VERSION 5.7 ;
  NOWIREEXTENSIONATPIN ON ;
  DIVIDERCHAR "/" ;
  BUSBITCHARS "[]" ;
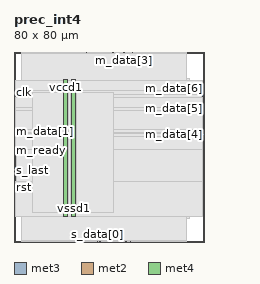
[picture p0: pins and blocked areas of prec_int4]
MACRO prec_int4
  CLASS BLOCK ;
  FOREIGN prec_int4 ;
  ORIGIN 0.000 0.000 ;
  SIZE 80.000 BY 80.000 ;
  PIN clk
    DIRECTION INPUT ;
    USE SIGNAL ;
    ANTENNAGATEAREA 1.286700 ;
    ANTENNADIFFAREA 0.434700 ;
    PORT
      LAYER met3 ;
        RECT 0.000 62.600 0.600 63.200 ;
    END
  END clk
  PIN m_data[0]
    DIRECTION OUTPUT ;
    USE SIGNAL ;
    ANTENNADIFFAREA 0.795200 ;
    PORT
      LAYER met2 ;
        RECT 41.490 79.720 41.770 80.000 ;
    END
  END m_data[0]
  PIN m_data[1]
    DIRECTION OUTPUT ;
    USE SIGNAL ;
    ANTENNADIFFAREA 0.795200 ;
    PORT
      LAYER met3 ;
        RECT 0.000 46.280 0.600 46.880 ;
    END
  END m_data[1]
  PIN m_data[2]
    DIRECTION OUTPUT ;
    USE SIGNAL ;
    ANTENNADIFFAREA 0.795200 ;
    PORT
      LAYER met2 ;
        RECT 30.450 79.720 30.730 80.000 ;
    END
  END m_data[2]
  PIN m_data[3]
    DIRECTION OUTPUT ;
    USE SIGNAL ;
    ANTENNADIFFAREA 0.795200 ;
    PORT
      LAYER met2 ;
        RECT 46.090 79.720 46.370 80.000 ;
    END
  END m_data[3]
  PIN m_data[4]
    DIRECTION OUTPUT ;
    USE SIGNAL ;
    ANTENNADIFFAREA 0.795200 ;
    PORT
      LAYER met3 ;
        RECT 79.400 44.920 80.000 45.520 ;
    END
  END m_data[4]
  PIN m_data[5]
    DIRECTION OUTPUT ;
    USE SIGNAL ;
    ANTENNADIFFAREA 0.795200 ;
    PORT
      LAYER met3 ;
        RECT 79.400 55.800 80.000 56.400 ;
    END
  END m_data[5]
  PIN m_data[6]
    DIRECTION OUTPUT ;
    USE SIGNAL ;
    ANTENNADIFFAREA 0.795200 ;
    PORT
      LAYER met3 ;
        RECT 79.400 61.240 80.000 61.840 ;
    END
  END m_data[6]
  PIN m_data[7]
    DIRECTION OUTPUT ;
    USE SIGNAL ;
    ANTENNADIFFAREA 0.795200 ;
    PORT
      LAYER met2 ;
        RECT 49.770 79.720 50.050 80.000 ;
    END
  END m_data[7]
  PIN m_last
    DIRECTION OUTPUT ;
    USE SIGNAL ;
    ANTENNADIFFAREA 0.795200 ;
    PORT
      LAYER met3 ;
        RECT 0.000 61.240 0.600 61.840 ;
    END
  END m_last
  PIN m_ready
    DIRECTION INPUT ;
    USE SIGNAL ;
    ANTENNAGATEAREA 0.647700 ;
    ANTENNADIFFAREA 0.434700 ;
    PORT
      LAYER met3 ;
        RECT 0.000 38.120 0.600 38.720 ;
    END
  END m_ready
  PIN m_valid
    DIRECTION OUTPUT ;
    USE SIGNAL ;
    ANTENNADIFFAREA 0.795200 ;
    PORT
      LAYER met3 ;
        RECT 0.000 35.400 0.600 36.000 ;
    END
  END m_valid
  PIN rst
    DIRECTION INPUT ;
    USE SIGNAL ;
    ANTENNAGATEAREA 0.631200 ;
    ANTENNADIFFAREA 0.434700 ;
    PORT
      LAYER met3 ;
        RECT 0.000 25.880 0.600 26.480 ;
    END
  END rst
  PIN s_data[0]
    DIRECTION INPUT ;
    USE SIGNAL ;
    ANTENNAGATEAREA 0.647700 ;
    ANTENNADIFFAREA 0.434700 ;
    PORT
      LAYER met2 ;
        RECT 35.050 0.000 35.330 0.280 ;
    END
  END s_data[0]
  PIN s_data[1]
    DIRECTION INPUT ;
    USE SIGNAL ;
    ANTENNAGATEAREA 0.647700 ;
    ANTENNADIFFAREA 0.434700 ;
    PORT
      LAYER met2 ;
        RECT 35.970 0.000 36.250 0.280 ;
    END
  END s_data[1]
  PIN s_data[2]
    DIRECTION INPUT ;
    USE SIGNAL ;
    ANTENNAGATEAREA 0.647700 ;
    ANTENNADIFFAREA 0.434700 ;
    PORT
      LAYER met2 ;
        RECT 47.010 0.000 47.290 0.280 ;
    END
  END s_data[2]
  PIN s_data[3]
    DIRECTION INPUT ;
    USE SIGNAL ;
    ANTENNAGATEAREA 0.647700 ;
    ANTENNADIFFAREA 0.434700 ;
    PORT
      LAYER met2 ;
        RECT 48.850 0.000 49.130 0.280 ;
    END
  END s_data[3]
  PIN s_data[4]
    DIRECTION INPUT ;
    USE SIGNAL ;
    ANTENNAGATEAREA 0.647700 ;
    ANTENNADIFFAREA 0.434700 ;
    PORT
      LAYER met3 ;
        RECT 0.000 34.040 0.600 34.640 ;
    END
  END s_data[4]
  PIN s_data[5]
    DIRECTION INPUT ;
    USE SIGNAL ;
    ANTENNAGATEAREA 0.647700 ;
    ANTENNADIFFAREA 0.434700 ;
    PORT
      LAYER met3 ;
        RECT 0.000 32.680 0.600 33.280 ;
    END
  END s_data[5]
  PIN s_data[6]
    DIRECTION INPUT ;
    USE SIGNAL ;
    ANTENNAGATEAREA 0.647700 ;
    ANTENNADIFFAREA 0.434700 ;
    PORT
      LAYER met3 ;
        RECT 0.000 27.240 0.600 27.840 ;
    END
  END s_data[6]
  PIN s_data[7]
    DIRECTION INPUT ;
    USE SIGNAL ;
    ANTENNAGATEAREA 0.647700 ;
    ANTENNADIFFAREA 0.434700 ;
    PORT
      LAYER met3 ;
        RECT 0.000 36.760 0.600 37.360 ;
    END
  END s_data[7]
  PIN s_last
    DIRECTION INPUT ;
    USE SIGNAL ;
    ANTENNAGATEAREA 0.647700 ;
    ANTENNADIFFAREA 0.434700 ;
    PORT
      LAYER met3 ;
        RECT 0.000 29.960 0.600 30.560 ;
    END
  END s_last
  PIN s_ready
    DIRECTION OUTPUT ;
    USE SIGNAL ;
    ANTENNADIFFAREA 0.795200 ;
    PORT
      LAYER met3 ;
        RECT 0.000 28.600 0.600 29.200 ;
    END
  END s_ready
  PIN s_valid
    DIRECTION INPUT ;
    USE SIGNAL ;
    ANTENNAGATEAREA 0.647700 ;
    ANTENNADIFFAREA 0.434700 ;
    PORT
      LAYER met3 ;
        RECT 0.000 31.320 0.600 31.920 ;
    END
  END s_valid
  PIN vccd1
    DIRECTION INOUT ;
    USE POWER ;
    PORT
      LAYER met4 ;
        RECT 21.040 10.640 22.640 68.240 ;
    END
  END vccd1
  PIN vssd1
    DIRECTION INOUT ;
    USE GROUND ;
    PORT
      LAYER met4 ;
        RECT 24.340 10.640 25.940 68.240 ;
    END
  END vssd1
  OBS
      LAYER nwell ;
        RECT 5.330 10.795 74.250 68.190 ;
      LAYER li1 ;
        RECT 5.520 10.795 74.060 68.085 ;
      LAYER met1 ;
        RECT 3.290 9.900 74.060 68.640 ;
      LAYER met2 ;
        RECT 3.310 79.440 30.170 79.720 ;
        RECT 31.010 79.440 41.210 79.720 ;
        RECT 42.050 79.440 45.810 79.720 ;
        RECT 46.650 79.440 49.490 79.720 ;
        RECT 50.330 79.440 72.590 79.720 ;
        RECT 3.310 0.560 72.590 79.440 ;
        RECT 3.310 0.280 34.770 0.560 ;
        RECT 35.610 0.280 35.690 0.560 ;
        RECT 36.530 0.280 46.730 0.560 ;
        RECT 47.570 0.280 48.570 0.560 ;
        RECT 49.410 0.280 72.590 0.560 ;
      LAYER met3 ;
        RECT 0.600 63.600 79.400 68.165 ;
        RECT 1.000 62.240 79.400 63.600 ;
        RECT 1.000 60.840 79.000 62.240 ;
        RECT 0.600 56.800 79.400 60.840 ;
        RECT 0.600 55.400 79.000 56.800 ;
        RECT 0.600 47.280 79.400 55.400 ;
        RECT 1.000 45.920 79.400 47.280 ;
        RECT 1.000 45.880 79.000 45.920 ;
        RECT 0.600 44.520 79.000 45.880 ;
        RECT 0.600 39.120 79.400 44.520 ;
        RECT 1.000 25.480 79.400 39.120 ;
        RECT 0.600 10.715 79.400 25.480 ;
      LAYER met4 ;
        RECT 7.655 12.415 20.640 63.065 ;
        RECT 23.040 12.415 23.940 63.065 ;
        RECT 26.340 12.415 42.025 63.065 ;
  END
END prec_int4
END LIBRARY

